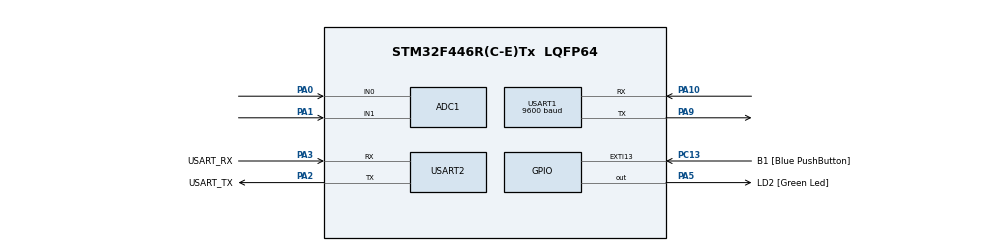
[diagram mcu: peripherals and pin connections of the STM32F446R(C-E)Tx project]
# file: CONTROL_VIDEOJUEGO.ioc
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ADC1.Channel-0\#ChannelRegularConversion=ADC_CHANNEL_0
ADC1.Channel-1\#ChannelRegularConversion=ADC_CHANNEL_1
ADC1.ContinuousConvMode=ENABLE
ADC1.DMAContinuousRequests=ENABLE
ADC1.NbrOfConversion=2
ADC1.NbrOfConversionFlag=1
ADC1.Rank-0\#ChannelRegularConversion=1
ADC1.Rank-1\#ChannelRegularConversion=2
ADC1.SamplingTime-0\#ChannelRegularConversion=ADC_SAMPLETIME_3CYCLES
ADC1.SamplingTime-1\#ChannelRegularConversion=ADC_SAMPLETIME_3CYCLES
ADC1.ScanConvMode=ENABLE
ADC1.master=1
Dma.ADC1.0.Direction=DMA_PERIPH_TO_MEMORY
Dma.ADC1.0.FIFOMode=DMA_FIFOMODE_DISABLE
Dma.ADC1.0.Instance=DMA2_Stream0
Dma.ADC1.0.MemDataAlignment=DMA_MDATAALIGN_HALFWORD
Dma.ADC1.0.MemInc=DMA_MINC_ENABLE
Dma.ADC1.0.Mode=DMA_CIRCULAR
Dma.ADC1.0.PeriphDataAlignment=DMA_PDATAALIGN_HALFWORD
Dma.ADC1.0.PeriphInc=DMA_PINC_DISABLE
Dma.ADC1.0.Priority=DMA_PRIORITY_LOW
Dma.Request0=ADC1
Mcu.Family=STM32F4
Mcu.Name=STM32F446R(C-E)Tx
Mcu.Package=LQFP64
NVIC.DMA2_Stream0_IRQn=true\:0\:0\:false\:false\:true\:false\:true\:true
NVIC.PriorityGroup=NVIC_PRIORITYGROUP_0
NVIC.USART1_IRQn=true\:0\:0\:false\:false\:true\:true\:true\:true
PA0-WKUP.Signal=ADCx_IN0
PA1.Signal=ADCx_IN1
PA10.Mode=Asynchronous
PA10.Signal=USART1_RX
PA13.GPIO_Label=TMS
PA13.Mode=Serial_Wire
PA13.Signal=SYS_JTMS-SWDIO
PA14.GPIO_Label=TCK
PA14.Mode=Serial_Wire
PA14.Signal=SYS_JTCK-SWCLK
PA2.GPIO_Label=USART_TX
PA2.Mode=Asynchronous
PA2.Signal=USART2_TX
PA3.GPIO_Label=USART_RX
PA3.Mode=Asynchronous
PA3.Signal=USART2_RX
PA5.GPIO_Label=LD2 [Green Led]
PA5.Signal=GPIO_Output
PA9.Mode=Asynchronous
PA9.Signal=USART1_TX
PB3.GPIO_Label=SWO
PB3.Signal=SYS_JTDO-SWO
PC13.GPIO_Label=B1 [Blue PushButton]
PC13.GPIO_ModeDefaultEXTI=GPIO_MODE_IT_FALLING
PC13.Signal=GPXTI13
PC14-OSC32_IN.Mode=LSE-External-Oscillator
PC14-OSC32_IN.Signal=RCC_OSC32_IN
PC15-OSC32_OUT.Mode=LSE-External-Oscillator
PC15-OSC32_OUT.Signal=RCC_OSC32_OUT
PH0-OSC_IN.Mode=HSE-External-Oscillator
PH0-OSC_IN.Signal=RCC_OSC_IN
PH1-OSC_OUT.Mode=HSE-External-Oscillator
PH1-OSC_OUT.Signal=RCC_OSC_OUT
ProjectManager.HeapSize=0x200
ProjectManager.StackSize=0x400
ProjectManager.TargetToolchain=STM32CubeIDE
RCC.48MHZClocksFreq_Value=84000000
RCC.AHBFreq_Value=84000000
RCC.APB1CLKDivider=RCC_HCLK_DIV2
RCC.APB1Freq_Value=42000000
RCC.APB1TimFreq_Value=84000000
RCC.APB2Freq_Value=84000000
RCC.APB2TimFreq_Value=84000000
RCC.CortexFreq_Value=84000000
RCC.FLatency-AdvancedSettings=FLASH_LATENCY_2
RCC.HCLKFreq_Value=84000000
RCC.HSE_VALUE=8000000
RCC.HSI_VALUE=16000000
RCC.PLLN=336
RCC.PLLP=RCC_PLLP_DIV4
RCC.SYSCLKFreq_VALUE=84000000
RCC.SYSCLKSource=RCC_SYSCLKSOURCE_PLLCLK
RCC.USBFreq_Value=168000000
RCC.VCOOutputFreq_Value=336000000
SH.ADCx_IN0.0=ADC1_IN0,IN0
SH.ADCx_IN1.0=ADC1_IN1,IN1
USART1.BaudRate=9600
USART1.VirtualMode=VM_ASYNC
USART2.VirtualMode=VM_ASYNC
board=NUCLEO-F446RE

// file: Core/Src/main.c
/* USER CODE BEGIN Header */
/**
  ******************************************************************************
  * @file           : main.c
  * @brief          : Main program body
  ******************************************************************************
  * @attention
  *
  * Copyright (c) 2026 STMicroelectronics.
  * All rights reserved.
  *
  * This software is licensed under terms that can be found in the LICENSE file
  * in the root directory of this software component.
  * If no LICENSE file comes with this software, it is provided AS-IS.
  *
  ******************************************************************************
  */
/* USER CODE END Header */
#include "main.h"

/* USER CODE BEGIN Includes */
#include <stdio.h>
#include <string.h>

/* USER CODE END Includes */

ADC_HandleTypeDef hadc1;
DMA_HandleTypeDef hdma_adc1;

UART_HandleTypeDef huart1;
UART_HandleTypeDef huart2;

/* USER CODE BEGIN PV */
volatile uint16_t ADC_value[2];

uint8_t temp;

/* USER CODE END PV */

void SystemClock_Config(void);
static void MX_GPIO_Init(void);
static void MX_DMA_Init(void);
static void MX_ADC1_Init(void);
static void MX_USART2_UART_Init(void);
static void MX_USART1_UART_Init(void);

int main(void)
{

  /* MCU Configuration--------------------------------------------------------*/

  /* Reset of all peripherals, Initializes the Flash interface and the Systick. */
  HAL_Init();

  /* Configure the system clock */
  SystemClock_Config();

  /* Initialize all configured peripherals */
  MX_GPIO_Init();
  MX_DMA_Init();
  MX_ADC1_Init();
  MX_USART2_UART_Init();
  MX_USART1_UART_Init();
  /* USER CODE BEGIN 2 */
  HAL_ADC_Start_DMA(&hadc1,(uint32_t *)ADC_value,2);
  HAL_UART_Receive_IT(&huart1, &temp,1);
  /* USER CODE END 2 */

  /* Infinite loop */
  while (1)
  {

    /* USER CODE BEGIN 3 */
	  HAL_Delay(500);
	  if(ADC_value[0]<1000)
	  {
		  char men[] ="STM arriba\r\n";
		  HAL_UART_Transmit(&huart2,(uint8_t*)men,strlen(men),1000);
	  }
	  else if(ADC_value[0]>3000)
	  {
		  char men[] = "STM abajo\r\n";
		  HAL_UART_Transmit(&huart2,(uint8_t*)men,strlen(men),1000);
	  }
	  if(ADC_value[1]>3000)
	  {
		  char men[] ="STM izquierda\r\n";
		  HAL_UART_Transmit(&huart2, (uint8_t*)men,strlen(men),1000);
	  }

	  else if(ADC_value[1]<1000)
	  {
		  char men[] ="STM derecha\r\n";
		  HAL_UART_Transmit(&huart2, (uint8_t*)men,strlen(men),1000);
	  }
  }
  /* USER CODE END 3 */
}

void SystemClock_Config(void)
{
  RCC_OscInitTypeDef RCC_OscInitStruct = {0};
  RCC_ClkInitTypeDef RCC_ClkInitStruct = {0};

  /** Configure the main internal regulator output voltage
  */
  __HAL_RCC_PWR_CLK_ENABLE();
  __HAL_PWR_VOLTAGESCALING_CONFIG(PWR_REGULATOR_VOLTAGE_SCALE3);

  /** Initializes the RCC Oscillators according to the specified parameters
  * in the RCC_OscInitTypeDef structure.
  */
  RCC_OscInitStruct.OscillatorType = RCC_OSCILLATORTYPE_HSI;
  RCC_OscInitStruct.HSIState = RCC_HSI_ON;
  RCC_OscInitStruct.HSICalibrationValue = RCC_HSICALIBRATION_DEFAULT;
  RCC_OscInitStruct.PLL.PLLState = RCC_PLL_ON;
  RCC_OscInitStruct.PLL.PLLSource = RCC_PLLSOURCE_HSI;
  RCC_OscInitStruct.PLL.PLLM = 8;
  RCC_OscInitStruct.PLL.PLLN = 64;
  RCC_OscInitStruct.PLL.PLLP = RCC_PLLP_DIV2;
  RCC_OscInitStruct.PLL.PLLQ = 2;
  RCC_OscInitStruct.PLL.PLLR = 2;
  if (HAL_RCC_OscConfig(&RCC_OscInitStruct) != HAL_OK)
  {
    Error_Handler();
  }

  /** Initializes the CPU, AHB and APB buses clocks
  */
  RCC_ClkInitStruct.ClockType = RCC_CLOCKTYPE_HCLK|RCC_CLOCKTYPE_SYSCLK
                              |RCC_CLOCKTYPE_PCLK1|RCC_CLOCKTYPE_PCLK2;
  RCC_ClkInitStruct.SYSCLKSource = RCC_SYSCLKSOURCE_PLLCLK;
  RCC_ClkInitStruct.AHBCLKDivider = RCC_SYSCLK_DIV1;
  RCC_ClkInitStruct.APB1CLKDivider = RCC_HCLK_DIV2;
  RCC_ClkInitStruct.APB2CLKDivider = RCC_HCLK_DIV8;

  if (HAL_RCC_ClockConfig(&RCC_ClkInitStruct, FLASH_LATENCY_2) != HAL_OK)
  {
    Error_Handler();
  }
}

static void MX_ADC1_Init(void)
{

  ADC_ChannelConfTypeDef sConfig = {0};

  /** Configure the global features of the ADC (Clock, Resolution, Data Alignment and number of conversion)
  */
  hadc1.Instance = ADC1;
  hadc1.Init.ClockPrescaler = ADC_CLOCK_SYNC_PCLK_DIV8;
  hadc1.Init.Resolution = ADC_RESOLUTION_12B;
  hadc1.Init.ScanConvMode = ENABLE;
  hadc1.Init.ContinuousConvMode = ENABLE;
  hadc1.Init.DiscontinuousConvMode = DISABLE;
  hadc1.Init.ExternalTrigConvEdge = ADC_EXTERNALTRIGCONVEDGE_NONE;
  hadc1.Init.ExternalTrigConv = ADC_SOFTWARE_START;
  hadc1.Init.DataAlign = ADC_DATAALIGN_RIGHT;
  hadc1.Init.NbrOfConversion = 2;
  hadc1.Init.DMAContinuousRequests = ENABLE;
  hadc1.Init.EOCSelection = ADC_EOC_SEQ_CONV;
  if (HAL_ADC_Init(&hadc1) != HAL_OK)
  {
    Error_Handler();
  }

  /** Configure for the selected ADC regular channel its corresponding rank in the sequencer and its sample time.
  */
  sConfig.Channel = ADC_CHANNEL_0;
  sConfig.Rank = 1;
  sConfig.SamplingTime = ADC_SAMPLETIME_56CYCLES;
  if (HAL_ADC_ConfigChannel(&hadc1, &sConfig) != HAL_OK)
  {
    Error_Handler();
  }

  /** Configure for the selected ADC regular channel its corresponding rank in the sequencer and its sample time.
  */
  sConfig.Channel = ADC_CHANNEL_1;
  sConfig.Rank = 2;
  sConfig.SamplingTime = ADC_SAMPLETIME_112CYCLES;
  if (HAL_ADC_ConfigChannel(&hadc1, &sConfig) != HAL_OK)
  {
    Error_Handler();
  }

}

static void MX_USART1_UART_Init(void)
{

  huart1.Instance = USART1;
  huart1.Init.BaudRate = 9600;
  huart1.Init.WordLength = UART_WORDLENGTH_8B;
  huart1.Init.StopBits = UART_STOPBITS_1;
  huart1.Init.Parity = UART_PARITY_NONE;
  huart1.Init.Mode = UART_MODE_TX_RX;
  huart1.Init.HwFlowCtl = UART_HWCONTROL_NONE;
  huart1.Init.OverSampling = UART_OVERSAMPLING_16;
  if (HAL_UART_Init(&huart1) != HAL_OK)
  {
    Error_Handler();
  }

}

static void MX_USART2_UART_Init(void)
{

  huart2.Instance = USART2;
  huart2.Init.BaudRate = 115200;
  huart2.Init.WordLength = UART_WORDLENGTH_8B;
  huart2.Init.StopBits = UART_STOPBITS_1;
  huart2.Init.Parity = UART_PARITY_NONE;
  huart2.Init.Mode = UART_MODE_TX_RX;
  huart2.Init.HwFlowCtl = UART_HWCONTROL_NONE;
  huart2.Init.OverSampling = UART_OVERSAMPLING_16;
  if (HAL_UART_Init(&huart2) != HAL_OK)
  {
    Error_Handler();
  }

}

static void MX_DMA_Init(void)
{

  /* DMA controller clock enable */
  __HAL_RCC_DMA2_CLK_ENABLE();

  /* DMA interrupt init */
  /* DMA2_Stream0_IRQn interrupt configuration */
  HAL_NVIC_SetPriority(DMA2_Stream0_IRQn, 0, 0);
  HAL_NVIC_EnableIRQ(DMA2_Stream0_IRQn);

}

static void MX_GPIO_Init(void)
{
  GPIO_InitTypeDef GPIO_InitStruct = {0};

  /* GPIO Ports Clock Enable */
  __HAL_RCC_GPIOC_CLK_ENABLE();
  __HAL_RCC_GPIOH_CLK_ENABLE();
  __HAL_RCC_GPIOA_CLK_ENABLE();
  __HAL_RCC_GPIOB_CLK_ENABLE();

  /*Configure GPIO pin Output Level */
  HAL_GPIO_WritePin(LD2_GPIO_Port, LD2_Pin, GPIO_PIN_RESET);

  /*Configure GPIO pin : B1_Pin */
  GPIO_InitStruct.Pin = B1_Pin;
  GPIO_InitStruct.Mode = GPIO_MODE_IT_FALLING;
  GPIO_InitStruct.Pull = GPIO_NOPULL;
  HAL_GPIO_Init(B1_GPIO_Port, &GPIO_InitStruct);

  /*Configure GPIO pin : LD2_Pin */
  GPIO_InitStruct.Pin = LD2_Pin;
  GPIO_InitStruct.Mode = GPIO_MODE_OUTPUT_PP;
  GPIO_InitStruct.Pull = GPIO_NOPULL;
  GPIO_InitStruct.Speed = GPIO_SPEED_FREQ_LOW;
  HAL_GPIO_Init(LD2_GPIO_Port, &GPIO_InitStruct);

}

/* USER CODE BEGIN 4 */
void HAL_ADC_ConvCpltCallback(ADC_HandleTypeDef *hadc)
{

}

void HAL_UART_RxCpltCallback(UART_HandleTypeDef *huart)
{
	if (huart->Instance == USART1) // Verifica que la interrupción sea del USART1
	    {
				if(temp == 'A'){
					HAL_UART_Transmit(&huart2, (uint8_t*)"ATMEGA ARRIBA\r\n", 14, 10);
				}
				else if(temp == 'B'){
					HAL_UART_Transmit(&huart2, (uint8_t*)"ATMEGA ABAJO\r\n", 13, 10);
				}
				else if(temp == 'C'){
					HAL_UART_Transmit(&huart2, (uint8_t*)"ATMEGA IZQUIERDA\r\n", 17, 10);
				}
				else if(temp == 'D'){
					HAL_UART_Transmit(&huart2, (uint8_t*)"ATMEGA DERECHA\r\n", 14, 10);
				}
				else if(temp == 'E'){
					HAL_UART_Transmit(&huart2, (uint8_t*)"ATMEGA A\r\n", 9, 10);
				}
				else if(temp == 'F'){
					HAL_UART_Transmit(&huart2, (uint8_t*)"ATMEGA B\r\n", 9, 10);
				}
				else {
					HAL_UART_Transmit(&huart2, (uint8_t*)"Comando desconocido\r\n", 21, 10);
				}
	        }
	 	 HAL_UART_Receive_IT(&huart1, &temp, 1);
	    }

/* USER CODE END 4 */

void Error_Handler(void)
{
  __disable_irq();
  while (1)
  {
  }
}
